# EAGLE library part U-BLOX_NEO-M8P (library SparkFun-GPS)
u-blox NEO-M8P The NEO-M8P module combines the high performance u-blox M8 positioning engine with u-blox’s Real Time Kinematic (RTK) technology. The NEO-M8P provides cm-level GNSS performance designed to meet the needs of unmanned vehicles and other machine control applications requiring high precision guidance.

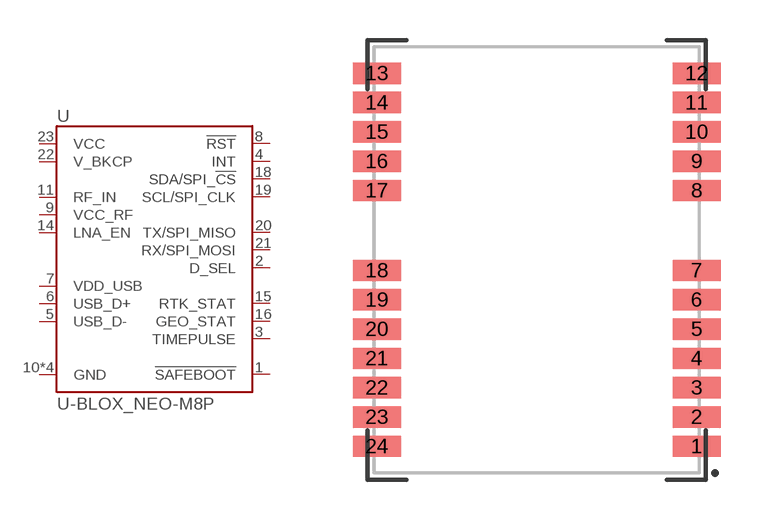
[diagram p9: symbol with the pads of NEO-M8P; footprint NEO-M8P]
Designator prefix U

## U-BLOX_NEO-M8PM8P (PROD_ID: IC-14069)  [NEO-M8P]
1  !SAFEBOOT!
2  D_SEL
3  TIMEPULSE
4  INT
5  USB_D-
6  USB_D+
7  VDD_USB
8  !RST
9  VCC_RF
10  GND
11  RF_IN
12  GND
13  GND
14  LNA_EN
15  RTK_STAT
16  GEO_STAT
18  SDA/SPI_!CS!
19  SCL/SPI_CLK
20  TX/SPI_MISO
21  RX/SPI_MOSI
22  V_BKCP
23  VCC
24  GND

## Footprint NEO-M8P (pad centres in mm)
smd 1.8 x 0.8: 1 6,-7; 2 6,-5.9; 3 6,-4.8; 4 6,-3.7; 5 6,-2.6; 6 6,-1.5; 7 6,-0.4; 8 6,2.6; 9 6,3.7; 10 6,4.8; 11 6,5.9; 12 6,7; 13 -6,7; 14 -6,5.9; 15 -6,4.8; 16 -6,3.7; 17 -6,2.6; 18 -6,-0.4; 19 -6,-1.5; 20 -6,-2.6; 21 -6,-3.7; 22 -6,-4.8; 23 -6,-5.9; 24 -6,-7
